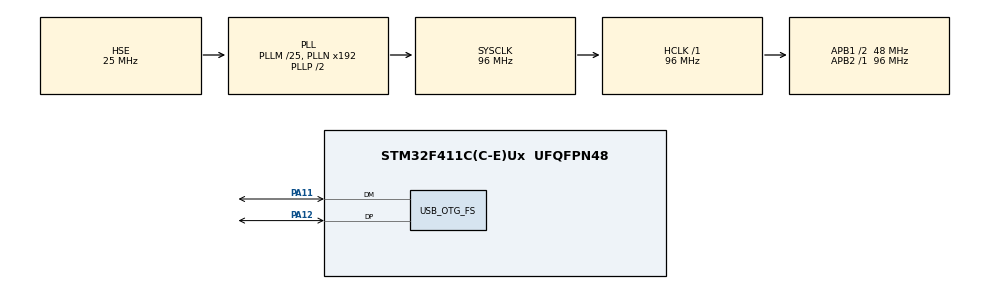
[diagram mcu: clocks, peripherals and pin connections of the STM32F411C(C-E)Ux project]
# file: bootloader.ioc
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Mcu.Family=STM32F4
USB_DEVICE.CLASS_NAME_FS=DFU
RCC.CortexFreq_Value=96000000
USB_DEVICE.VirtualModeFS=Dfu_FS
PH1\ -\ OSC_OUT.Mode=HSE-External-Oscillator
PA11.Mode=Device_Only
RCC.APB1CLKDivider=RCC_HCLK_DIV2
VP_USB_DEVICE_VS_USB_DEVICE_DFU_FS.Mode=DFU_FS
RCC.SYSCLKSource=RCC_SYSCLKSOURCE_PLLCLK
ProjectManager.StackSize=0x400
PA13.Signal=SYS_JTMS-SWDIO
USB_DEVICE.MANUFACTURER_STRING=OptDyn
PA12.Signal=USB_OTG_FS_DP
PH0\ -\ OSC_IN.Mode=HSE-External-Oscillator
PH0\ -\ OSC_IN.Signal=RCC_OSC_IN
ProjectManager.TargetToolchain=STM32CubeIDE
RCC.HCLKFreq_Value=96000000
RCC.APB2TimFreq_Value=96000000
USB_DEVICE.PRODUCT_STRING_DFU_FS=LifeLine DownLoad Firmware Update
RCC.LSE_VALUE=32768
RCC.AHBFreq_Value=96000000
RCC.HSE_VALUE=25000000
PH1\ -\ OSC_OUT.Signal=RCC_OSC_OUT
board=custom
RCC.VCOOutputFreq_Value=192000000
RCC.APB2Freq_Value=96000000
PA14.Mode=Serial_Wire
USB_OTG_FS.Sof_enable=ENABLE
PA13.Mode=Serial_Wire
Mcu.Name=STM32F411C(C-E)Ux
RCC.48MHZClocksFreq_Value=48000000
RCC.SYSCLKFreq_VALUE=96000000
Mcu.Package=UFQFPN48
PA12.Mode=Device_Only
NVIC.OTG_FS_IRQn=true\:0\:0\:false\:false\:true\:false\:true
PA11.Signal=USB_OTG_FS_DM
PA14.Signal=SYS_JTCK-SWCLK
USB_OTG_FS.VirtualMode=Device_Only
ProjectManager.HeapSize=0x200
RCC.HSI_VALUE=16000000
NVIC.PriorityGroup=NVIC_PRIORITYGROUP_4
RCC.PLLM=25
RCC.APB1TimFreq_Value=96000000
RCC.APB1Freq_Value=48000000
USB_DEVICE.VirtualMode=Dfu

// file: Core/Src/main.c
/* USER CODE BEGIN Header */
/**
  ******************************************************************************
  * @file           : main.c
  * @brief          : Main program body
  ******************************************************************************
  * @attention
  *
  * <h2><center>&copy; Copyright (c) 2021 STMicroelectronics.
  * All rights reserved.</center></h2>
  *
  * This software component is licensed by ST under BSD 3-Clause license,
  * the "License"; You may not use this file except in compliance with the
  * License. You may obtain a copy of the License at:
  *                        opensource.org/licenses/BSD-3-Clause
  *
  ******************************************************************************
  */
/* USER CODE END Header */
#include "main.h"
#include "usb_device.h"

void SystemClock_Config(void);
static void MX_GPIO_Init(void);

int main(void)
{

  /* MCU Configuration--------------------------------------------------------*/

  /* Reset of all peripherals, Initializes the Flash interface and the Systick. */
  HAL_Init();

  /* Configure the system clock */
  SystemClock_Config();

  /* Initialize all configured peripherals */
  MX_GPIO_Init();
  MX_USB_DEVICE_Init();

  /* Infinite loop */
  /* USER CODE BEGIN WHILE */

  uint32_t now = 0, then = 0;

  while (1)
  {

	now = HAL_GetTick();
	if (now % 100 == 0 && now != then) {

		HAL_GPIO_TogglePin(LED_GPIO_Port, LED_Pin);

		then = now;
	}

    /* USER CODE END WHILE */

  }
}

void SystemClock_Config(void)
{
  RCC_OscInitTypeDef RCC_OscInitStruct = {0};
  RCC_ClkInitTypeDef RCC_ClkInitStruct = {0};

  /** Configure the main internal regulator output voltage
  */
  __HAL_RCC_PWR_CLK_ENABLE();
  __HAL_PWR_VOLTAGESCALING_CONFIG(PWR_REGULATOR_VOLTAGE_SCALE1);
  /** Initializes the RCC Oscillators according to the specified parameters
  * in the RCC_OscInitTypeDef structure.
  */
  RCC_OscInitStruct.OscillatorType = RCC_OSCILLATORTYPE_HSE;
  RCC_OscInitStruct.HSEState = RCC_HSE_ON;
  RCC_OscInitStruct.PLL.PLLState = RCC_PLL_ON;
  RCC_OscInitStruct.PLL.PLLSource = RCC_PLLSOURCE_HSE;
  RCC_OscInitStruct.PLL.PLLM = 25;
  RCC_OscInitStruct.PLL.PLLN = 192;
  RCC_OscInitStruct.PLL.PLLP = RCC_PLLP_DIV2;
  RCC_OscInitStruct.PLL.PLLQ = 4;
  if (HAL_RCC_OscConfig(&RCC_OscInitStruct) != HAL_OK)
  {
    Error_Handler();
  }
  /** Initializes the CPU, AHB and APB buses clocks
  */
  RCC_ClkInitStruct.ClockType = RCC_CLOCKTYPE_HCLK|RCC_CLOCKTYPE_SYSCLK
                              |RCC_CLOCKTYPE_PCLK1|RCC_CLOCKTYPE_PCLK2;
  RCC_ClkInitStruct.SYSCLKSource = RCC_SYSCLKSOURCE_PLLCLK;
  RCC_ClkInitStruct.AHBCLKDivider = RCC_SYSCLK_DIV1;
  RCC_ClkInitStruct.APB1CLKDivider = RCC_HCLK_DIV2;
  RCC_ClkInitStruct.APB2CLKDivider = RCC_HCLK_DIV1;

  if (HAL_RCC_ClockConfig(&RCC_ClkInitStruct, FLASH_LATENCY_3) != HAL_OK)
  {
    Error_Handler();
  }
}

static void MX_GPIO_Init(void)
{
  GPIO_InitTypeDef GPIO_InitStruct = {0};

  /* GPIO Ports Clock Enable */
  __HAL_RCC_GPIOC_CLK_ENABLE();
  __HAL_RCC_GPIOH_CLK_ENABLE();
  __HAL_RCC_GPIOA_CLK_ENABLE();

  /*Configure GPIO pin Output Level */
  HAL_GPIO_WritePin(LED_GPIO_Port, LED_Pin, GPIO_PIN_SET);

  /*Configure GPIO pin : LED_Pin */
  GPIO_InitStruct.Pin = LED_Pin;
  GPIO_InitStruct.Mode = GPIO_MODE_OUTPUT_OD;
  GPIO_InitStruct.Pull = GPIO_NOPULL;
  GPIO_InitStruct.Speed = GPIO_SPEED_FREQ_LOW;
  HAL_GPIO_Init(LED_GPIO_Port, &GPIO_InitStruct);

  /*Configure GPIO pin : BTN_Pin */
  GPIO_InitStruct.Pin = BTN_Pin;
  GPIO_InitStruct.Mode = GPIO_MODE_IT_FALLING;
  GPIO_InitStruct.Pull = GPIO_PULLUP;
  HAL_GPIO_Init(BTN_GPIO_Port, &GPIO_InitStruct);

}

void Error_Handler(void)
{
  __disable_irq();
  while (1)
  {
  }
}

/************************ (C) COPYRIGHT STMicroelectronics *****END OF FILE****/
